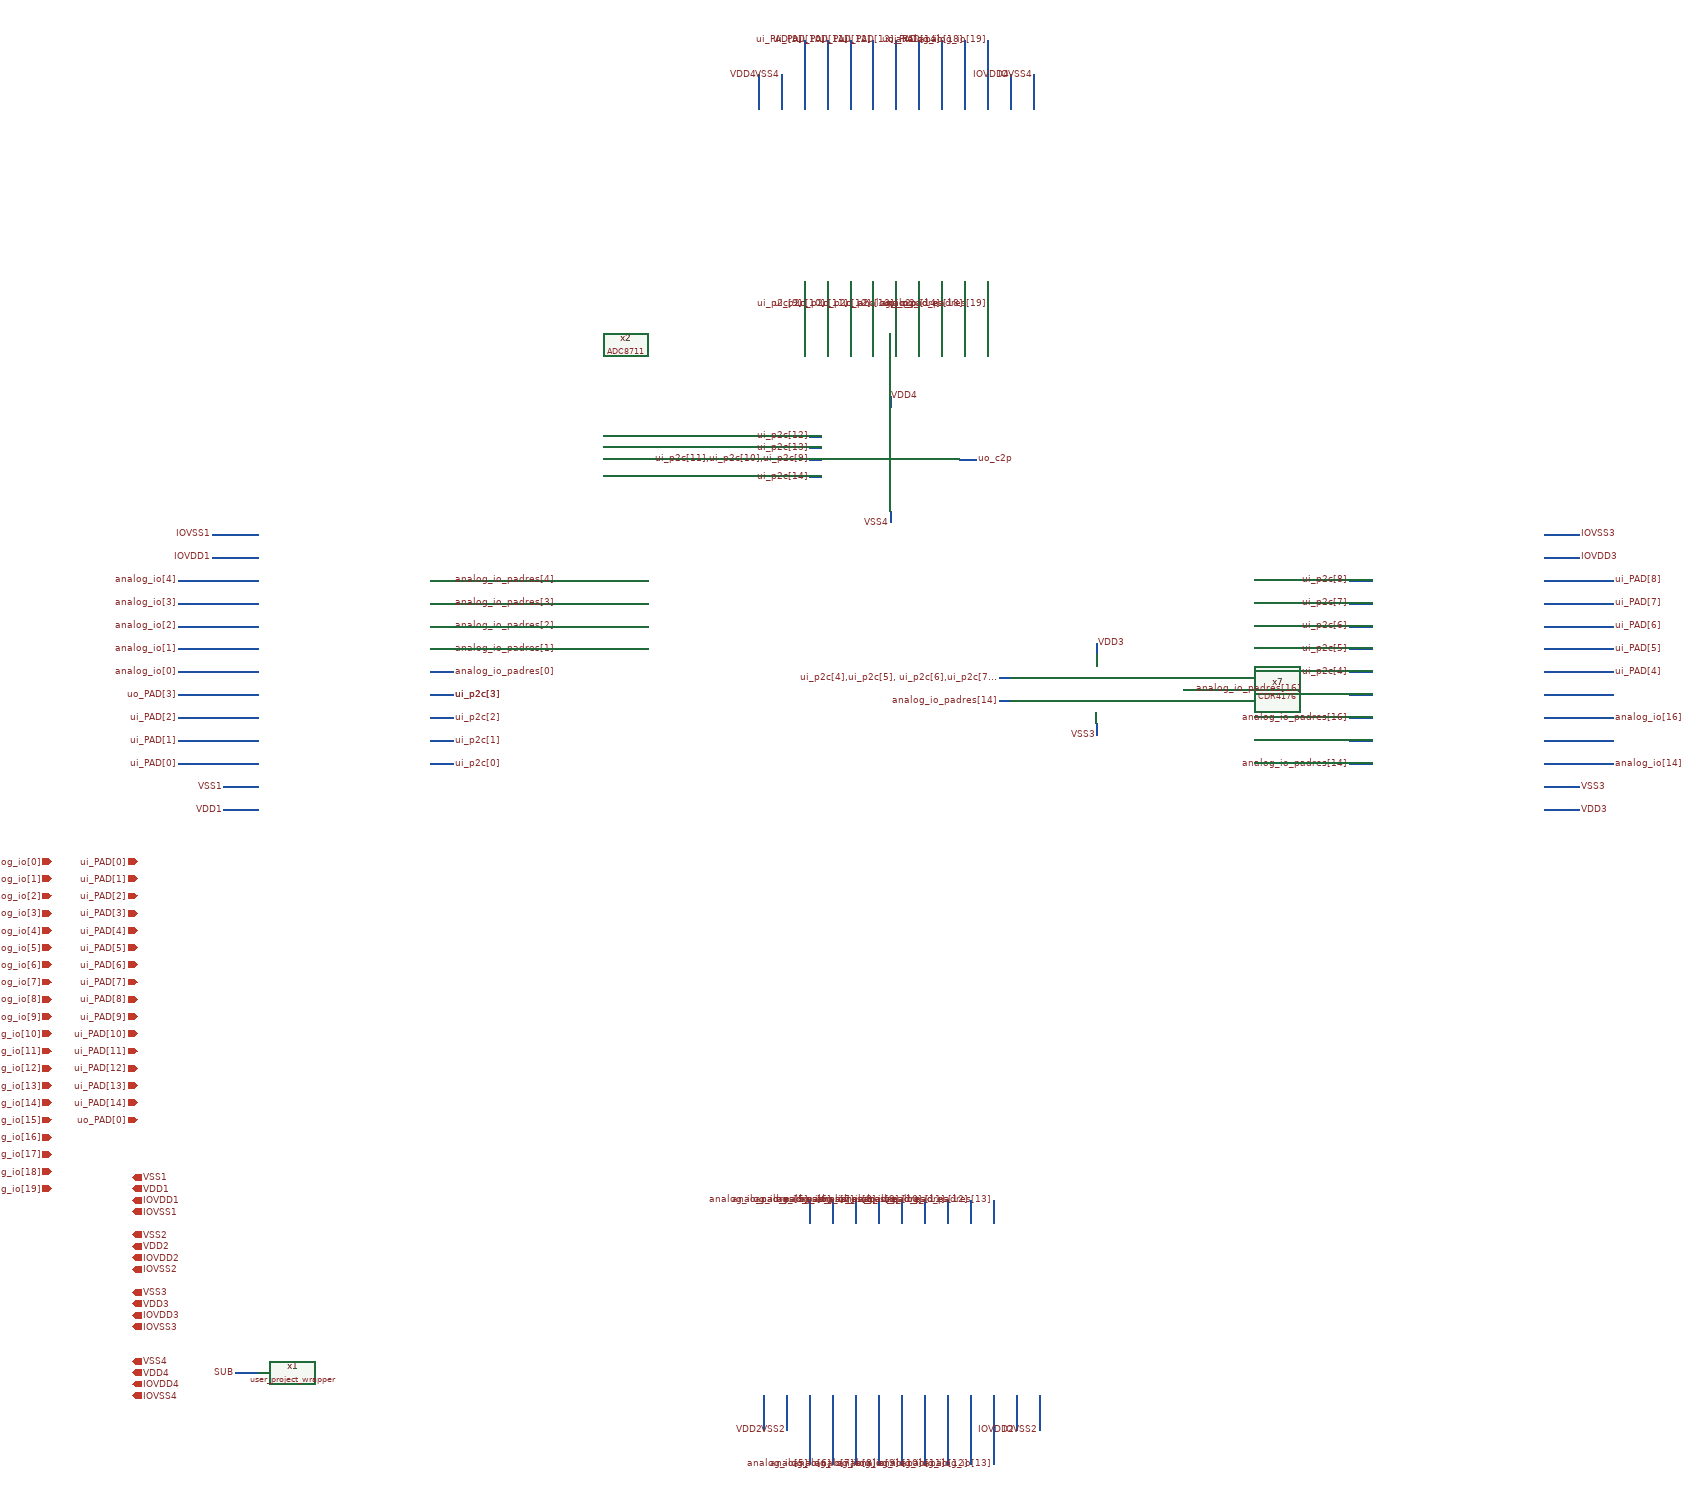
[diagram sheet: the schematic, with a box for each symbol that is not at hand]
v {xschem version=3.4.8RC file_version=1.2}
G {}
K {}
V {}
S {}
F {}
E {}
N 300 -1180 340 -1180 {lab=ui_p2c[2]}
N 300 -1220 340 -1220 {lab=ui_p2c[3]}
N 300 -1420 340 -1420 {lab=analog_io_padres[4]}
N 2240 -1500 2300 -1500 {lab=IOVSS4}
N 2240 -1460 2300 -1460 {lab=IOVDD4}
N 2240 -1420 2360 -1420 {lab=ui_PAD[8]}
N 2240 -1100 2360 -1100 {lab=analog_io[14]}
N 2240 -1380 2360 -1380 {lab=ui_PAD[7]}
N 2240 -1260 2360 -1260 {lab=ui_PAD[4]}
N 2240 -1140 2360 -1140 {lab=#net1}
N 960 0 960 120 {lab=analog_io[5]}
N 1000 0 1000 120 {lab=analog_io[6]}
N 1040 0 1040 120 {lab=analog_io[7]}
N 1080 0 1080 120 {lab=analog_io[8]}
N 1120 0 1120 120 {lab=analog_io[9]}
N 1160 0 1160 120 {lab=analog_io[10]}
N 1200 0 1200 120 {lab=analog_io[11]}
N 1240 0 1240 120 {lab=analog_io[12]}
N 1280 0 1280 120 {lab=analog_io[13]}
N -40 -40 0 -40 {lab=SUB}
N 2240 -1340 2360 -1340 {lab=ui_PAD[6]}
N 2240 -1300 2360 -1300 {lab=ui_PAD[5]}
N 2240 -1180 2360 -1180 {lab=analog_io[16]}
N 2240 -1220 2360 -1220 {lab=#net2}
N 300 -1380 340 -1380 {lab=analog_io_padres[3]}
N 300 -1340 340 -1340 {lab=analog_io_padres[2]}
N 300 -1300 340 -1300 {lab=analog_io_padres[1]}
N 300 -1260 340 -1260 {lab=analog_io_padres[0]}
N 300 -1140 340 -1140 {lab=ui_p2c[1]}
N 300 -1100 340 -1100 {lab=ui_p2c[0]}
N -140 -1420 0 -1420 {lab=analog_io[4]}
N -140 -1380 0 -1380 {lab=analog_io[3]}
N -140 -1340 0 -1340 {lab=analog_io[2]}
N -140 -1300 0 -1300 {lab=analog_io[1]}
N -140 -1260 0 -1260 {lab=analog_io[0]}
N -140 -1220 0 -1220 {lab=uo_PAD[3]}
N -140 -1180 0 -1180 {lab=ui_PAD[2]}
N -140 -1140 0 -1140 {lab=ui_PAD[1]}
N -140 -1100 0 -1100 {lab=ui_PAD[0]}
N 1000 -340 1000 -300 {lab=analog_io_padres[6]}
N 1040 -340 1040 -300 {lab=analog_io_padres[7]}
N 1080 -340 1080 -300 {lab=analog_io_padres[8]}
N 1120 -340 1120 -300 {lab=analog_io_padres[9]}
N 1160 -340 1160 -300 {lab=analog_io_padres[10]}
N 1200 -340 1200 -300 {lab=analog_io_padres[11]}
N 1240 -340 1240 -300 {lab=analog_io_padres[12]}
N 1280 -340 1280 -300 {lab=analog_io_padres[13]}
N 960 -340 960 -300 {lab=analog_io_padres[5]}
N -80 -1500 -0 -1500 {lab=IOVSS4}
N -80 -1460 -0 -1460 {lab=IOVDD4}
N -60 -1060 -0 -1060 {lab=VSS4}
N -60 -1020 -0 -1020 {lab=VDD4}
N 880 0 880 60 {lab=VDD4}
N 920 0 920 60 {lab=VSS4}
N 1320 0 1320 60 {lab=IOVDD4}
N 1360 0 1360 60 {lab=IOVSS4}
N 2240 -1020 2300 -1020 {lab=VDD4}
N 2240 -1060 2300 -1060 {lab=VSS4}
N 1900 -1100 1940 -1100 {lab=analog_io_padres[14]}
N 1900 -1140 1940 -1140 {lab=#net3}
N 1900 -1180 1940 -1180 {lab=analog_io_padres[16]}
N 1900 -1220 1940 -1220 {lab=#net4}
N 1900 -1420 1940 -1420 {lab=ui_p2c[8]}
N 1900 -1380 1940 -1380 {lab=ui_p2c[7]}
N 1900 -1340 1940 -1340 {lab=ui_p2c[6]}
N 1900 -1300 1940 -1300 {lab=ui_p2c[5]}
N 1900 -1260 1940 -1260 {lab=ui_p2c[4]}
N 870 -2300 870 -2240 {lab=VDD4}
N 910 -2300 910 -2240 {lab=VSS4}
N 950 -2360 950 -2240 {lab=ui_PAD[9]}
N 990 -2360 990 -2240 {lab=ui_PAD[10]}
N 1030 -2360 1030 -2240 {lab=ui_PAD[11]}
N 1070 -2360 1070 -2240 {lab=ui_PAD[12]}
N 1110 -2360 1110 -2240 {lab=ui_PAD[13]}
N 1150 -2360 1150 -2240 {lab=uo_PAD}
N 1190 -2360 1190 -2240 {lab=ui_PAD[14]}
N 1230 -2360 1230 -2240 {lab=analog_io[18]}
N 1270 -2360 1270 -2240 {lab=analog_io[19]}
N 1310 -2300 1310 -2240 {lab=IOVDD4}
N 1350 -2300 1350 -2240 {lab=IOVSS4}
N 950 -1940 950 -1900 {lab=ui_p2c[9]}
N 990 -1940 990 -1900 {lab=ui_p2c[10]}
N 1030 -1940 1030 -1900 {lab=ui_p2c[11]}
N 1070 -1940 1070 -1900 {lab=ui_p2c[12]}
N 1110 -1940 1110 -1900 {lab=ui_p2c[13]}
N 1150 -1940 1150 -1900 {lab=uo_c2p}
N 1190 -1940 1190 -1900 {lab=ui_p2c[14]}
N 1230 -1940 1230 -1900 {lab=analog_io_padres[18]}
N 1270 -1940 1270 -1900 {lab=analog_io_padres[19]}
N 1610 -1230 1630 -1230 {lab=analog_io_padres[16]}
N 1290 -1210 1310 -1210 {lab=analog_io_padres[14]}
N 1290 -1250 1310 -1250 {lab=ui_p2c[4],ui_p2c[5],ui_p2c[6],ui_p2c[7],ui_p2c[8]}
N 1460 -1310 1460 -1290 {lab=VDD3}
N 1460 -1170 1460 -1150 {lab=VSS3}
N 1100 -1740 1100 -1720 {lab=VDD4}
N 1100 -1540 1100 -1520 {lab=VSS4}
N 960 -1600 980 -1600 {lab=ui_p2c[14]}
N 1220 -1630 1250 -1630 {lab=uo_c2p}
N 960 -1650 980 -1650 {lab=ui_p2c[13]}
N 960 -1670 980 -1670 {lab=ui_p2c[12]}
N 960 -1630 980 -1630 {lab=ui_p2c[9]}
C {lab_wire.sym} 1030 -2360 3 1 {name=p12 sig_type=std_logic lab=ui_PAD[11]	}
C {lab_wire.sym} 990 -2360 3 1 {name=p13 sig_type=std_logic lab=ui_PAD[10]	}
C {lab_wire.sym} 1230 -2360 3 1 {name=p14 sig_type=std_logic lab=analog_io[18]	}
C {lab_wire.sym} 1190 -2360 3 1 {name=p15 sig_type=std_logic lab=ui_PAD[14]	}
C {lab_wire.sym} 1070 -2360 3 1 {name=p16 sig_type=std_logic lab=ui_PAD[12]	}
C {lab_wire.sym} 950 -2360 3 1 {name=p17 sig_type=std_logic lab=ui_PAD[9]	}
C {lab_wire.sym} 1110 -2360 3 1 {name=p18 sig_type=std_logic lab=ui_PAD[13]	}
C {lab_wire.sym} 1150 -2360 3 1 {name=p19 sig_type=std_logic lab=uo_PAD	}
C {lab_wire.sym} 1270 -2360 3 1 {name=p20 sig_type=std_logic lab=analog_io[19]	}
C {lab_wire.sym} 1350 -2300 3 1 {name=p21 sig_type=std_logic lab=IOVSS4	}
C {lab_wire.sym} 1310 -2300 3 1 {name=p22 sig_type=std_logic lab=IOVDD4	}
C {lab_wire.sym} 910 -2300 3 1 {name=p23 sig_type=std_logic lab=VSS4}
C {lab_wire.sym} 870 -2300 3 1 {name=p24 sig_type=std_logic lab=VDD4	}
C {lab_wire.sym} 1230 -1900 3 0 {name=p29 sig_type=std_logic lab=analog_io_padres[18]	}
C {lab_wire.sym} 340 -1220 0 1 {name=p42 sig_type=std_logic lab=ui_p2c[3]	}
C {lab_wire.sym} 340 -1340 0 1 {name=p45 sig_type=std_logic lab=analog_io_padres[2]	}
C {lab_wire.sym} 340 -1300 0 1 {name=p46 sig_type=std_logic lab=analog_io_padres[1]	}
C {lab_wire.sym} -140 -1420 0 0 {name=p59 sig_type=std_logic lab=analog_io[4]	}
C {lab_wire.sym} 2300 -1060 0 1 {name=p63 sig_type=std_logic lab=VSS3}
C {lab_wire.sym} 2300 -1020 0 1 {name=p64 sig_type=std_logic lab=VDD3}
C {lab_wire.sym} 2360 -1180 0 1 {name=p67 sig_type=std_logic lab=analog_io[16]}
C {lab_wire.sym} 2360 -1340 0 1 {name=p68 sig_type=std_logic lab=ui_PAD[6]}
C {lab_wire.sym} 1900 -1100 0 0 {name=p72 sig_type=std_logic lab=analog_io_padres[14]}
C {noconn.sym} 2360 -1140 2 0 {name=l4}
C {lab_wire.sym} 2300 -1500 0 1 {name=p75 sig_type=std_logic lab=IOVSS3}
C {lab_wire.sym} 2300 -1460 0 1 {name=p76 sig_type=std_logic lab=IOVDD3}
C {lab_wire.sym} 2360 -1380 0 1 {name=p77 sig_type=std_logic lab=ui_PAD[7]	}
C {lab_wire.sym} 2360 -1260 0 1 {name=p78 sig_type=std_logic lab=ui_PAD[4]	}
C {lab_wire.sym} 2360 -1100 0 1 {name=p79 sig_type=std_logic lab=analog_io[14]	}
C {lab_wire.sym} 1360 60 3 0 {name=p80 sig_type=std_logic lab=IOVSS2}
C {lab_wire.sym} 1320 60 3 0 {name=p81 sig_type=std_logic lab=IOVDD2}
C {lab_wire.sym} 920 60 3 0 {name=p82 sig_type=std_logic lab=VSS2}
C {lab_wire.sym} 880 60 3 0 {name=p83 sig_type=std_logic lab=VDD2}
C {lab_wire.sym} 1000 120 3 0 {name=p84 sig_type=std_logic lab=analog_io[6]	}
C {lab_wire.sym} 1040 120 3 0 {name=p85 sig_type=std_logic lab=analog_io[7]	}
C {lab_wire.sym} 1080 120 3 0 {name=p86 sig_type=std_logic lab=analog_io[8]	}
C {lab_wire.sym} 1120 120 3 0 {name=p87 sig_type=std_logic lab=analog_io[9]	}
C {lab_wire.sym} 1160 120 3 0 {name=p88 sig_type=std_logic lab=analog_io[10]	}
C {lab_wire.sym} 1200 120 3 0 {name=p89 sig_type=std_logic lab=analog_io[11]	}
C {lab_wire.sym} 1240 120 3 0 {name=p90 sig_type=std_logic lab=analog_io[12]	}
C {lab_wire.sym} 1280 120 3 0 {name=p91 sig_type=std_logic lab=analog_io[13]	}
C {lab_wire.sym} 960 120 3 0 {name=p102 sig_type=std_logic lab=analog_io[5]	}
C {lab_pin.sym} 960 -340 1 0 {name=p111 sig_type=std_logic lab=analog_io_padres[5]}
C {lab_pin.sym} 1000 -340 1 0 {name=p112 sig_type=std_logic lab=analog_io_padres[6]}
C {lab_pin.sym} 1040 -340 1 0 {name=p113 sig_type=std_logic lab=analog_io_padres[7]}
C {lab_pin.sym} 1080 -340 1 0 {name=p117 sig_type=std_logic lab=analog_io_padres[8]}
C {iopin.sym} -360 -660 2 0 {name=p98 lab=analog_io[9]}
C {iopin.sym} -360 -630 2 0 {name=p103 lab=analog_io[10]}
C {iopin.sym} -360 -810 2 0 {name=p104 lab=analog_io[4]}
C {iopin.sym} -360 -930 2 0 {name=p105 lab=analog_io[0]}
C {iopin.sym} -360 -900 2 0 {name=p106 lab=analog_io[1]}
C {iopin.sym} -360 -780 2 0 {name=p116 lab=analog_io[5]}
C {iopin.sym} -360 -750 2 0 {name=p107 lab=analog_io[6]}
C {iopin.sym} -360 -720 2 0 {name=p118 lab=analog_io[7]}
C {iopin.sym} -360 -600 2 0 {name=p119 lab=analog_io[11]}
C {iopin.sym} -360 -570 2 0 {name=p120 lab=analog_io[12]}
C {iopin.sym} -360 -540 2 0 {name=p121 lab=analog_io[13]}
C {iopin.sym} -360 -510 2 0 {name=p122 lab=analog_io[14]}
C {iopin.sym} -360 -480 2 0 {name=p123 lab=analog_io[15]}
C {iopin.sym} -360 -450 2 0 {name=p124 lab=analog_io[16]}
C {iopin.sym} -360 -420 2 0 {name=p125 lab=analog_io[17]}
C {iopin.sym} -360 -360 2 0 {name=p127 lab=analog_io[19]}
C {iopin.sym} -360 -690 2 0 {name=p128 lab=analog_io[8]}
C {iopin.sym} -210 -930 2 0 {name=p129 lab=ui_PAD[0]}
C {iopin.sym} -210 -900 2 0 {name=p131 lab=ui_PAD[1]}
C {iopin.sym} -210 -840 2 0 {name=p132 lab=ui_PAD[3]}
C {iopin.sym} -210 -810 2 0 {name=p134 lab=ui_PAD[4]}
C {iopin.sym} -360 -390 2 0 {name=p136 lab=analog_io[18]}
C {iopin.sym} -210 -780 2 0 {name=p137 lab=ui_PAD[5]}
C {iopin.sym} -210 -720 2 0 {name=p138 lab=ui_PAD[7]}
C {iopin.sym} -360 -870 2 0 {name=p139 lab=analog_io[2]}
C {iopin.sym} -360 -840 2 0 {name=p140 lab=analog_io[3]}
C {iopin.sym} -210 -690 2 0 {name=p141 lab=ui_PAD[8]}
C {iopin.sym} -210 -750 2 0 {name=p108 lab=ui_PAD[6]}
C {iopin.sym} -210 -480 2 0 {name=p114 lab=uo_PAD[0]}
C {iopin.sym} -210 -870 2 0 {name=p142 lab=ui_PAD[2]}
C {iopin.sym} -220 -380 0 1 {name=p130 lab=VSS1}
C {iopin.sym} -220 -360 0 1 {name=p133 lab=VDD1}
C {iopin.sym} -220 -340 0 1 {name=p135 lab=IOVDD1}
C {iopin.sym} -220 -320 0 1 {name=p143 lab=IOVSS1}
C {iopin.sym} -220 -60 0 1 {name=p144 lab=VSS4}
C {iopin.sym} -220 -40 0 1 {name=p145 lab=VDD4}
C {iopin.sym} -220 -20 0 1 {name=p146 lab=IOVDD4}
C {iopin.sym} -220 0 0 1 {name=p147 lab=IOVSS4}
C {iopin.sym} -220 -280 0 1 {name=p148 lab=VSS2}
C {iopin.sym} -220 -260 0 1 {name=p149 lab=VDD2}
C {iopin.sym} -220 -240 0 1 {name=p150 lab=IOVDD2}
C {iopin.sym} -220 -220 0 1 {name=p151 lab=IOVSS2}
C {iopin.sym} -220 -180 0 1 {name=p152 lab=VSS3}
C {iopin.sym} -220 -160 0 1 {name=p153 lab=VDD3}
C {iopin.sym} -220 -140 0 1 {name=p154 lab=IOVDD3}
C {iopin.sym} -220 -120 0 1 {name=p155 lab=IOVSS3}
C {lab_wire.sym} -40 -40 0 0 {name=p156 sig_type=std_logic lab=SUB}
C {noconn.sym} 1900 -1220 0 0 {name=l2}
C {lab_wire.sym} -140 -1380 0 0 {name=p159 sig_type=std_logic lab=analog_io[3]	}
C {lab_wire.sym} -140 -1260 0 0 {name=p160 sig_type=std_logic lab=analog_io[0]	}
C {lab_wire.sym} -60 -1020 0 0 {name=p161 sig_type=std_logic lab=VDD1}
C {lab_wire.sym} -60 -1060 0 0 {name=p162 sig_type=std_logic lab=VSS1}
C {lab_wire.sym} -140 -1100 0 0 {name=p163 sig_type=std_logic lab=ui_PAD[0]	}
C {lab_wire.sym} -140 -1140 0 0 {name=p164 sig_type=std_logic lab=ui_PAD[1]	}
C {lab_wire.sym} -140 -1180 0 0 {name=p165 sig_type=std_logic lab=ui_PAD[2]	}
C {lab_wire.sym} -140 -1220 0 0 {name=p166 sig_type=std_logic lab=uo_PAD[3]	}
C {lab_wire.sym} -140 -1300 0 0 {name=p167 sig_type=std_logic lab=analog_io[1]	}
C {lab_wire.sym} -140 -1340 0 0 {name=p168 sig_type=std_logic lab=analog_io[2]	}
C {lab_wire.sym} -80 -1500 0 0 {name=p170 sig_type=std_logic lab=IOVSS1	}
C {lab_wire.sym} -80 -1460 0 0 {name=p171 sig_type=std_logic lab=IOVDD1}
C {/foss/designs/IHP__MPC2585/MPC2585-main/schematic/xschem/user_project_wrapper.sym} 0 0 0 0 {name=x1}
C {noconn.sym} 2360 -1220 2 0 {name=l5}
C {iopin.sym} -210 -660 2 0 {name=p172 lab=ui_PAD[9]}
C {iopin.sym} -210 -630 2 0 {name=p173 lab=ui_PAD[10]}
C {iopin.sym} -210 -600 2 0 {name=p174 lab=ui_PAD[11]}
C {iopin.sym} -210 -570 2 0 {name=p175 lab=ui_PAD[12]}
C {iopin.sym} -210 -540 2 0 {name=p176 lab=ui_PAD[13]}
C {iopin.sym} -210 -510 2 0 {name=p177 lab=ui_PAD[14]}
C {CDR4176/CDR4176.sym} 1460 -1230 0 0 {name=x7}
C {/foss/designs/IHP__ADC8711/ADC8711-main/schematic/xschem/ADC8711.sym} 960 -1520 0 0 {name=x2}
C {lab_wire.sym} 2360 -1300 0 1 {name=p9 sig_type=std_logic lab=ui_PAD[5]}
C {lab_wire.sym} 2360 -1420 0 1 {name=p25 sig_type=std_logic lab=ui_PAD[8]	}
C {lab_wire.sym} 340 -1420 0 1 {name=p30 sig_type=std_logic lab=analog_io_padres[4]	}
C {lab_wire.sym} 340 -1380 0 1 {name=p31 sig_type=std_logic lab=analog_io_padres[3]	}
C {lab_wire.sym} 340 -1260 0 1 {name=p53 sig_type=std_logic lab=analog_io_padres[0]	}
C {lab_wire.sym} 340 -1180 0 1 {name=p54 sig_type=std_logic lab=ui_p2c[2]	}
C {lab_wire.sym} 340 -1140 0 1 {name=p36 sig_type=std_logic lab=ui_p2c[1]	}
C {lab_wire.sym} 340 -1100 0 1 {name=p37 sig_type=std_logic lab=ui_p2c[0]	}
C {lab_pin.sym} 1120 -340 1 0 {name=p3 sig_type=std_logic lab=analog_io_padres[9]}
C {lab_pin.sym} 1160 -340 1 0 {name=p28 sig_type=std_logic lab=analog_io_padres[10]}
C {lab_pin.sym} 1200 -340 1 0 {name=p32 sig_type=std_logic lab=analog_io_padres[11]}
C {lab_pin.sym} 1240 -340 1 0 {name=p33 sig_type=std_logic lab=analog_io_padres[12]}
C {lab_pin.sym} 1280 -340 1 0 {name=p34 sig_type=std_logic lab=analog_io_padres[13]}
C {noconn.sym} 1900 -1140 0 0 {name=l1}
C {lab_wire.sym} 1900 -1180 0 0 {name=p35 sig_type=std_logic lab=analog_io_padres[16]}
C {lab_wire.sym} 340 -1220 0 1 {name=p38 sig_type=std_logic lab=ui_p2c[3]	}
C {lab_wire.sym} 1900 -1260 0 0 {name=p39 sig_type=std_logic lab=ui_p2c[4]	}
C {lab_wire.sym} 1900 -1300 0 0 {name=p40 sig_type=std_logic lab=ui_p2c[5]	}
C {lab_wire.sym} 1900 -1340 0 0 {name=p43 sig_type=std_logic lab=ui_p2c[6]	}
C {lab_wire.sym} 1900 -1380 0 0 {name=p44 sig_type=std_logic lab=ui_p2c[7]	}
C {lab_wire.sym} 1900 -1420 0 0 {name=p47 sig_type=std_logic lab=ui_p2c[8]	}
C {lab_wire.sym} 950 -1900 3 0 {name=p10 sig_type=std_logic lab=ui_p2c[9]	}
C {lab_wire.sym} 1150 -1900 3 0 {name=p48 sig_type=std_logic lab=uo_c2p	}
C {lab_wire.sym} 990 -1900 3 0 {name=p49 sig_type=std_logic lab=ui_p2c[10]	}
C {lab_wire.sym} 1030 -1900 3 0 {name=p51 sig_type=std_logic lab=ui_p2c[11]	}
C {lab_wire.sym} 1070 -1900 3 0 {name=p52 sig_type=std_logic lab=ui_p2c[12]	}
C {lab_wire.sym} 1110 -1900 3 0 {name=p2 sig_type=std_logic lab=ui_p2c[13]	}
C {lab_wire.sym} 1190 -1900 3 0 {name=p27 sig_type=std_logic lab=ui_p2c[14]	}
C {lab_wire.sym} 1270 -1900 3 0 {name=p55 sig_type=std_logic lab=analog_io_padres[19]	}
C {lab_wire.sym} 1630 -1230 0 1 {name=p1 sig_type=std_logic lab=analog_io_padres[16]}
C {lab_wire.sym} 1290 -1210 0 0 {name=p4 sig_type=std_logic lab=analog_io_padres[14]}
C {lab_wire.sym} 1290 -1250 0 0 {name=p5 sig_type=std_logic lab="ui_p2c[4],ui_p2c[5],
ui_p2c[6],ui_p2c[7],
ui_p2c[8]"	}
C {lab_wire.sym} 1460 -1310 0 1 {name=p6 sig_type=std_logic lab=VDD3}
C {lab_wire.sym} 1460 -1150 2 1 {name=p7 sig_type=std_logic lab=VSS3}
C {lab_wire.sym} 1100 -1740 0 1 {name=p8 sig_type=std_logic lab=VDD4	}
C {lab_wire.sym} 1100 -1520 2 1 {name=p11 sig_type=std_logic lab=VSS4}
C {lab_wire.sym} 960 -1600 2 1 {name=p26 sig_type=std_logic lab=ui_p2c[14]	}
C {lab_wire.sym} 1250 -1630 2 0 {name=p41 sig_type=std_logic lab=uo_c2p	}
C {lab_wire.sym} 960 -1650 0 0 {name=p50 sig_type=std_logic lab=ui_p2c[13]	}
C {lab_wire.sym} 960 -1670 0 0 {name=p56 sig_type=std_logic lab=ui_p2c[12]	}
C {lab_wire.sym} 960 -1630 2 1 {name=p57 sig_type=std_logic lab="ui_p2c[11],ui_p2c[10],ui_p2c[9]"	}
